# Generated by innovus_enablement/scripts/gen_fakeram.py: abstract 256x16 SRAM.
# Geometry is an assumption (see script header), not PDK data.
VERSION 5.8 ;
BUSBITCHARS "[]" ;
DIVIDERCHAR "/" ;

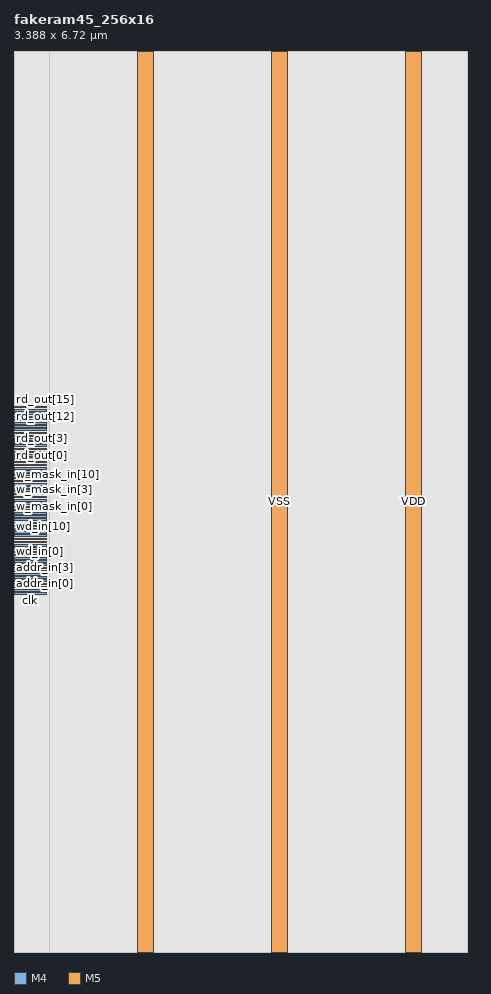
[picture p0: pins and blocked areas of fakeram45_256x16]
MACRO fakeram45_256x16
  CLASS BLOCK ;
  FOREIGN fakeram45_256x16 0 0 ;
  ORIGIN 0 0 ;
  SIZE 3.3880 BY 6.7200 ;
  SYMMETRY X Y R90 ;
  PIN clk
    DIRECTION INPUT ;
    USE CLOCK ;
    PORT
      LAYER M4 ;
        RECT 0 2.6700 0.2400 2.6820 ;
    END
  END clk
  PIN ce_in
    DIRECTION INPUT ;
    USE SIGNAL ;
    PORT
      LAYER M4 ;
        RECT 0 2.6940 0.2400 2.7060 ;
    END
  END ce_in
  PIN we_in
    DIRECTION INPUT ;
    USE SIGNAL ;
    PORT
      LAYER M4 ;
        RECT 0 2.7180 0.2400 2.7300 ;
    END
  END we_in
  PIN addr_in[0]
    DIRECTION INPUT ;
    USE SIGNAL ;
    PORT
      LAYER M4 ;
        RECT 0 2.7420 0.2400 2.7540 ;
    END
  END addr_in[0]
  PIN addr_in[1]
    DIRECTION INPUT ;
    USE SIGNAL ;
    PORT
      LAYER M4 ;
        RECT 0 2.7660 0.2400 2.7780 ;
    END
  END addr_in[1]
  PIN addr_in[2]
    DIRECTION INPUT ;
    USE SIGNAL ;
    PORT
      LAYER M4 ;
        RECT 0 2.7900 0.2400 2.8020 ;
    END
  END addr_in[2]
  PIN addr_in[3]
    DIRECTION INPUT ;
    USE SIGNAL ;
    PORT
      LAYER M4 ;
        RECT 0 2.8140 0.2400 2.8260 ;
    END
  END addr_in[3]
  PIN addr_in[4]
    DIRECTION INPUT ;
    USE SIGNAL ;
    PORT
      LAYER M4 ;
        RECT 0 2.8380 0.2400 2.8500 ;
    END
  END addr_in[4]
  PIN addr_in[5]
    DIRECTION INPUT ;
    USE SIGNAL ;
    PORT
      LAYER M4 ;
        RECT 0 2.8620 0.2400 2.8740 ;
    END
  END addr_in[5]
  PIN addr_in[6]
    DIRECTION INPUT ;
    USE SIGNAL ;
    PORT
      LAYER M4 ;
        RECT 0 2.8860 0.2400 2.8980 ;
    END
  END addr_in[6]
  PIN addr_in[7]
    DIRECTION INPUT ;
    USE SIGNAL ;
    PORT
      LAYER M4 ;
        RECT 0 2.9100 0.2400 2.9220 ;
    END
  END addr_in[7]
  PIN wd_in[0]
    DIRECTION INPUT ;
    USE SIGNAL ;
    PORT
      LAYER M4 ;
        RECT 0 2.9340 0.2400 2.9460 ;
    END
  END wd_in[0]
  PIN wd_in[1]
    DIRECTION INPUT ;
    USE SIGNAL ;
    PORT
      LAYER M4 ;
        RECT 0 2.9580 0.2400 2.9700 ;
    END
  END wd_in[1]
  PIN wd_in[2]
    DIRECTION INPUT ;
    USE SIGNAL ;
    PORT
      LAYER M4 ;
        RECT 0 2.9820 0.2400 2.9940 ;
    END
  END wd_in[2]
  PIN wd_in[3]
    DIRECTION INPUT ;
    USE SIGNAL ;
    PORT
      LAYER M4 ;
        RECT 0 3.0060 0.2400 3.0180 ;
    END
  END wd_in[3]
  PIN wd_in[4]
    DIRECTION INPUT ;
    USE SIGNAL ;
    PORT
      LAYER M4 ;
        RECT 0 3.0300 0.2400 3.0420 ;
    END
  END wd_in[4]
  PIN wd_in[5]
    DIRECTION INPUT ;
    USE SIGNAL ;
    PORT
      LAYER M4 ;
        RECT 0 3.0540 0.2400 3.0660 ;
    END
  END wd_in[5]
  PIN wd_in[6]
    DIRECTION INPUT ;
    USE SIGNAL ;
    PORT
      LAYER M4 ;
        RECT 0 3.0780 0.2400 3.0900 ;
    END
  END wd_in[6]
  PIN wd_in[7]
    DIRECTION INPUT ;
    USE SIGNAL ;
    PORT
      LAYER M4 ;
        RECT 0 3.1020 0.2400 3.1140 ;
    END
  END wd_in[7]
  PIN wd_in[8]
    DIRECTION INPUT ;
    USE SIGNAL ;
    PORT
      LAYER M4 ;
        RECT 0 3.1260 0.2400 3.1380 ;
    END
  END wd_in[8]
  PIN wd_in[9]
    DIRECTION INPUT ;
    USE SIGNAL ;
    PORT
      LAYER M4 ;
        RECT 0 3.1500 0.2400 3.1620 ;
    END
  END wd_in[9]
  PIN wd_in[10]
    DIRECTION INPUT ;
    USE SIGNAL ;
    PORT
      LAYER M4 ;
        RECT 0 3.1740 0.2400 3.1860 ;
    END
  END wd_in[10]
  PIN wd_in[11]
    DIRECTION INPUT ;
    USE SIGNAL ;
    PORT
      LAYER M4 ;
        RECT 0 3.1980 0.2400 3.2100 ;
    END
  END wd_in[11]
  PIN wd_in[12]
    DIRECTION INPUT ;
    USE SIGNAL ;
    PORT
      LAYER M4 ;
        RECT 0 3.2220 0.2400 3.2340 ;
    END
  END wd_in[12]
  PIN wd_in[13]
    DIRECTION INPUT ;
    USE SIGNAL ;
    PORT
      LAYER M4 ;
        RECT 0 3.2460 0.2400 3.2580 ;
    END
  END wd_in[13]
  PIN wd_in[14]
    DIRECTION INPUT ;
    USE SIGNAL ;
    PORT
      LAYER M4 ;
        RECT 0 3.2700 0.2400 3.2820 ;
    END
  END wd_in[14]
  PIN wd_in[15]
    DIRECTION INPUT ;
    USE SIGNAL ;
    PORT
      LAYER M4 ;
        RECT 0 3.2940 0.2400 3.3060 ;
    END
  END wd_in[15]
  PIN w_mask_in[0]
    DIRECTION INPUT ;
    USE SIGNAL ;
    PORT
      LAYER M4 ;
        RECT 0 3.3180 0.2400 3.3300 ;
    END
  END w_mask_in[0]
  PIN w_mask_in[1]
    DIRECTION INPUT ;
    USE SIGNAL ;
    PORT
      LAYER M4 ;
        RECT 0 3.3420 0.2400 3.3540 ;
    END
  END w_mask_in[1]
  PIN w_mask_in[2]
    DIRECTION INPUT ;
    USE SIGNAL ;
    PORT
      LAYER M4 ;
        RECT 0 3.3660 0.2400 3.3780 ;
    END
  END w_mask_in[2]
  PIN w_mask_in[3]
    DIRECTION INPUT ;
    USE SIGNAL ;
    PORT
      LAYER M4 ;
        RECT 0 3.3900 0.2400 3.4020 ;
    END
  END w_mask_in[3]
  PIN w_mask_in[4]
    DIRECTION INPUT ;
    USE SIGNAL ;
    PORT
      LAYER M4 ;
        RECT 0 3.4140 0.2400 3.4260 ;
    END
  END w_mask_in[4]
  PIN w_mask_in[5]
    DIRECTION INPUT ;
    USE SIGNAL ;
    PORT
      LAYER M4 ;
        RECT 0 3.4380 0.2400 3.4500 ;
    END
  END w_mask_in[5]
  PIN w_mask_in[6]
    DIRECTION INPUT ;
    USE SIGNAL ;
    PORT
      LAYER M4 ;
        RECT 0 3.4620 0.2400 3.4740 ;
    END
  END w_mask_in[6]
  PIN w_mask_in[7]
    DIRECTION INPUT ;
    USE SIGNAL ;
    PORT
      LAYER M4 ;
        RECT 0 3.4860 0.2400 3.4980 ;
    END
  END w_mask_in[7]
  PIN w_mask_in[8]
    DIRECTION INPUT ;
    USE SIGNAL ;
    PORT
      LAYER M4 ;
        RECT 0 3.5100 0.2400 3.5220 ;
    END
  END w_mask_in[8]
  PIN w_mask_in[9]
    DIRECTION INPUT ;
    USE SIGNAL ;
    PORT
      LAYER M4 ;
        RECT 0 3.5340 0.2400 3.5460 ;
    END
  END w_mask_in[9]
  PIN w_mask_in[10]
    DIRECTION INPUT ;
    USE SIGNAL ;
    PORT
      LAYER M4 ;
        RECT 0 3.5580 0.2400 3.5700 ;
    END
  END w_mask_in[10]
  PIN w_mask_in[11]
    DIRECTION INPUT ;
    USE SIGNAL ;
    PORT
      LAYER M4 ;
        RECT 0 3.5820 0.2400 3.5940 ;
    END
  END w_mask_in[11]
  PIN w_mask_in[12]
    DIRECTION INPUT ;
    USE SIGNAL ;
    PORT
      LAYER M4 ;
        RECT 0 3.6060 0.2400 3.6180 ;
    END
  END w_mask_in[12]
  PIN w_mask_in[13]
    DIRECTION INPUT ;
    USE SIGNAL ;
    PORT
      LAYER M4 ;
        RECT 0 3.6300 0.2400 3.6420 ;
    END
  END w_mask_in[13]
  PIN w_mask_in[14]
    DIRECTION INPUT ;
    USE SIGNAL ;
    PORT
      LAYER M4 ;
        RECT 0 3.6540 0.2400 3.6660 ;
    END
  END w_mask_in[14]
  PIN w_mask_in[15]
    DIRECTION INPUT ;
    USE SIGNAL ;
    PORT
      LAYER M4 ;
        RECT 0 3.6780 0.2400 3.6900 ;
    END
  END w_mask_in[15]
  PIN rd_out[0]
    DIRECTION OUTPUT ;
    USE SIGNAL ;
    PORT
      LAYER M4 ;
        RECT 0 3.7020 0.2400 3.7140 ;
    END
  END rd_out[0]
  PIN rd_out[1]
    DIRECTION OUTPUT ;
    USE SIGNAL ;
    PORT
      LAYER M4 ;
        RECT 0 3.7260 0.2400 3.7380 ;
    END
  END rd_out[1]
  PIN rd_out[2]
    DIRECTION OUTPUT ;
    USE SIGNAL ;
    PORT
      LAYER M4 ;
        RECT 0 3.7500 0.2400 3.7620 ;
    END
  END rd_out[2]
  PIN rd_out[3]
    DIRECTION OUTPUT ;
    USE SIGNAL ;
    PORT
      LAYER M4 ;
        RECT 0 3.7740 0.2400 3.7860 ;
    END
  END rd_out[3]
  PIN rd_out[4]
    DIRECTION OUTPUT ;
    USE SIGNAL ;
    PORT
      LAYER M4 ;
        RECT 0 3.7980 0.2400 3.8100 ;
    END
  END rd_out[4]
  PIN rd_out[5]
    DIRECTION OUTPUT ;
    USE SIGNAL ;
    PORT
      LAYER M4 ;
        RECT 0 3.8220 0.2400 3.8340 ;
    END
  END rd_out[5]
  PIN rd_out[6]
    DIRECTION OUTPUT ;
    USE SIGNAL ;
    PORT
      LAYER M4 ;
        RECT 0 3.8460 0.2400 3.8580 ;
    END
  END rd_out[6]
  PIN rd_out[7]
    DIRECTION OUTPUT ;
    USE SIGNAL ;
    PORT
      LAYER M4 ;
        RECT 0 3.8700 0.2400 3.8820 ;
    END
  END rd_out[7]
  PIN rd_out[8]
    DIRECTION OUTPUT ;
    USE SIGNAL ;
    PORT
      LAYER M4 ;
        RECT 0 3.8940 0.2400 3.9060 ;
    END
  END rd_out[8]
  PIN rd_out[9]
    DIRECTION OUTPUT ;
    USE SIGNAL ;
    PORT
      LAYER M4 ;
        RECT 0 3.9180 0.2400 3.9300 ;
    END
  END rd_out[9]
  PIN rd_out[10]
    DIRECTION OUTPUT ;
    USE SIGNAL ;
    PORT
      LAYER M4 ;
        RECT 0 3.9420 0.2400 3.9540 ;
    END
  END rd_out[10]
  PIN rd_out[11]
    DIRECTION OUTPUT ;
    USE SIGNAL ;
    PORT
      LAYER M4 ;
        RECT 0 3.9660 0.2400 3.9780 ;
    END
  END rd_out[11]
  PIN rd_out[12]
    DIRECTION OUTPUT ;
    USE SIGNAL ;
    PORT
      LAYER M4 ;
        RECT 0 3.9900 0.2400 4.0020 ;
    END
  END rd_out[12]
  PIN rd_out[13]
    DIRECTION OUTPUT ;
    USE SIGNAL ;
    PORT
      LAYER M4 ;
        RECT 0 4.0140 0.2400 4.0260 ;
    END
  END rd_out[13]
  PIN rd_out[14]
    DIRECTION OUTPUT ;
    USE SIGNAL ;
    PORT
      LAYER M4 ;
        RECT 0 4.0380 0.2400 4.0500 ;
    END
  END rd_out[14]
  PIN rd_out[15]
    DIRECTION OUTPUT ;
    USE SIGNAL ;
    PORT
      LAYER M4 ;
        RECT 0 4.0620 0.2400 4.0740 ;
    END
  END rd_out[15]
  PIN VDD
    DIRECTION INOUT ;
    USE POWER ;
    PORT
      LAYER M5 ;
        RECT 0.9200 0 1.0400 6.7200 ;
        RECT 2.9200 0 3.0400 6.7200 ;
    END
  END VDD
  PIN VSS
    DIRECTION INOUT ;
    USE GROUND ;
    PORT
      LAYER M5 ;
        RECT 1.9200 0 2.0400 6.7200 ;
    END
  END VSS
  OBS
    LAYER M0 ;
      RECT 0 0 3.3880 6.7200 ;
    LAYER M1 ;
      RECT 0 0 3.3880 6.7200 ;
    LAYER M2 ;
      RECT 0 0 3.3880 6.7200 ;
    LAYER M3 ;
      RECT 0 0 3.3880 6.7200 ;
    LAYER VIA0 ;
      RECT 0 0 3.3880 6.7200 ;
    LAYER VIA1 ;
      RECT 0 0 3.3880 6.7200 ;
    LAYER VIA2 ;
      RECT 0 0 3.3880 6.7200 ;
    LAYER VIA3 ;
      RECT 0 0 3.3880 6.7200 ;
    LAYER M4 ;
      RECT 0.2640 0 3.3880 6.7200 ;
  END
END fakeram45_256x16

END LIBRARY
